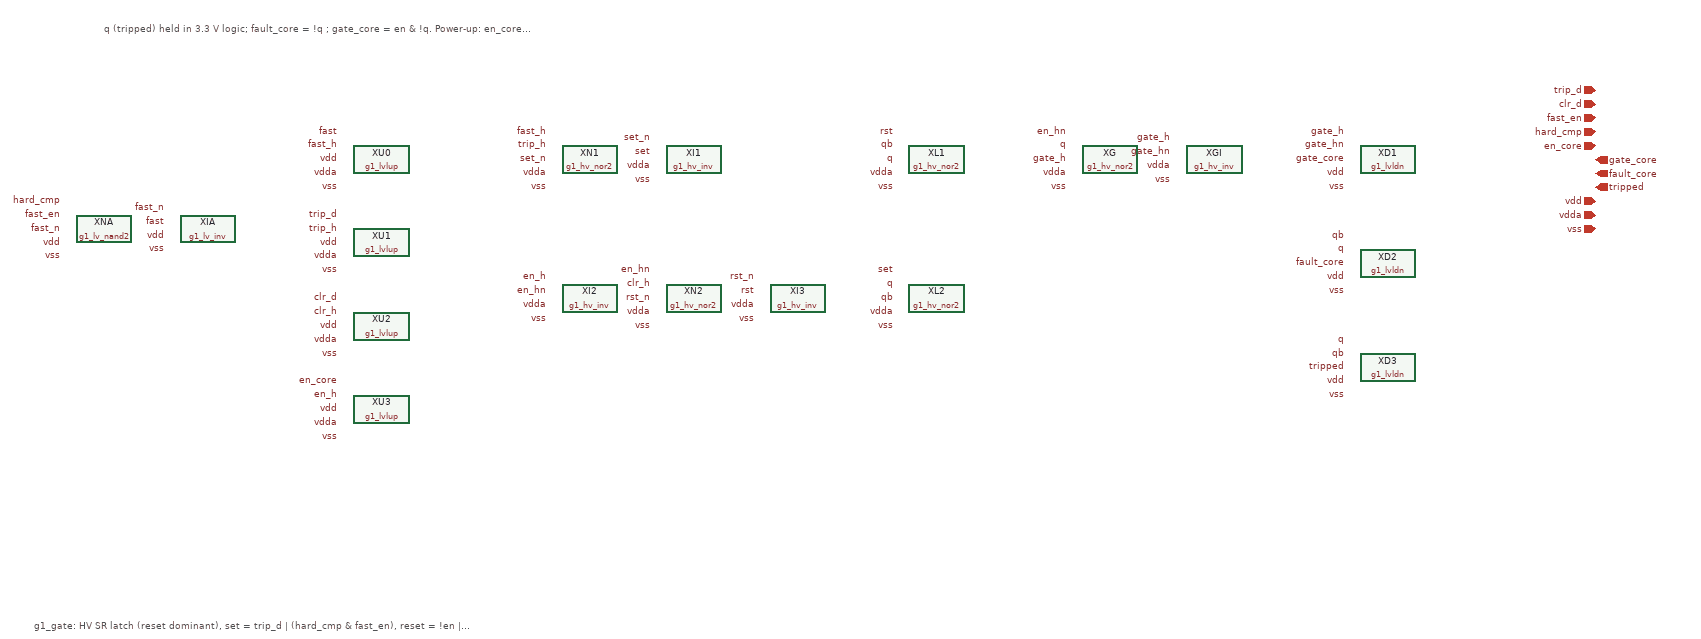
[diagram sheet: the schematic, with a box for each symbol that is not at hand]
v {xschem version=3.4.8RC file_version=1.3}
G {}
K {}
V {}
S {}
E {}
T {g1_gate: HV SR latch (reset dominant), set = trip_d | (hard_cmp & fast_en), reset = !en | clr_d} 0 -40 0 0 0.4 0.4 {}
C {g1_lv_nand2.sym} 100 -600 0 0 {name=XNA }
C {devices/lab_pin.sym} 40 -640 0 0 {name=l1 lab=hard_cmp}
C {devices/lab_pin.sym} 40 -620 0 0 {name=l2 lab=fast_en}
C {devices/lab_pin.sym} 40 -600 0 0 {name=l3 lab=fast_n}
C {devices/lab_pin.sym} 40 -580 0 0 {name=l4 lab=vdd}
C {devices/lab_pin.sym} 40 -560 0 0 {name=l5 lab=vss}
C {g1_lv_inv.sym} 250 -600 0 0 {name=XIA }
C {devices/lab_pin.sym} 190 -630 0 0 {name=l6 lab=fast_n}
C {devices/lab_pin.sym} 190 -610 0 0 {name=l7 lab=fast}
C {devices/lab_pin.sym} 190 -590 0 0 {name=l8 lab=vdd}
C {devices/lab_pin.sym} 190 -570 0 0 {name=l9 lab=vss}
C {g1_lvlup.sym} 500 -700 0 0 {name=XU0 }
C {devices/lab_pin.sym} 440 -740 0 0 {name=l10 lab=fast}
C {devices/lab_pin.sym} 440 -720 0 0 {name=l11 lab=fast_h}
C {devices/lab_pin.sym} 440 -700 0 0 {name=l12 lab=vdd}
C {devices/lab_pin.sym} 440 -680 0 0 {name=l13 lab=vdda}
C {devices/lab_pin.sym} 440 -660 0 0 {name=l14 lab=vss}
C {g1_lvlup.sym} 500 -580 0 0 {name=XU1 }
C {devices/lab_pin.sym} 440 -620 0 0 {name=l15 lab=trip_d}
C {devices/lab_pin.sym} 440 -600 0 0 {name=l16 lab=trip_h}
C {devices/lab_pin.sym} 440 -580 0 0 {name=l17 lab=vdd}
C {devices/lab_pin.sym} 440 -560 0 0 {name=l18 lab=vdda}
C {devices/lab_pin.sym} 440 -540 0 0 {name=l19 lab=vss}
C {g1_lvlup.sym} 500 -460 0 0 {name=XU2 }
C {devices/lab_pin.sym} 440 -500 0 0 {name=l20 lab=clr_d}
C {devices/lab_pin.sym} 440 -480 0 0 {name=l21 lab=clr_h}
C {devices/lab_pin.sym} 440 -460 0 0 {name=l22 lab=vdd}
C {devices/lab_pin.sym} 440 -440 0 0 {name=l23 lab=vdda}
C {devices/lab_pin.sym} 440 -420 0 0 {name=l24 lab=vss}
C {g1_lvlup.sym} 500 -340 0 0 {name=XU3 }
C {devices/lab_pin.sym} 440 -380 0 0 {name=l25 lab=en_core}
C {devices/lab_pin.sym} 440 -360 0 0 {name=l26 lab=en_h}
C {devices/lab_pin.sym} 440 -340 0 0 {name=l27 lab=vdd}
C {devices/lab_pin.sym} 440 -320 0 0 {name=l28 lab=vdda}
C {devices/lab_pin.sym} 440 -300 0 0 {name=l29 lab=vss}
C {g1_hv_nor2.sym} 800 -700 0 0 {name=XN1 }
C {devices/lab_pin.sym} 740 -740 0 0 {name=l30 lab=fast_h}
C {devices/lab_pin.sym} 740 -720 0 0 {name=l31 lab=trip_h}
C {devices/lab_pin.sym} 740 -700 0 0 {name=l32 lab=set_n}
C {devices/lab_pin.sym} 740 -680 0 0 {name=l33 lab=vdda}
C {devices/lab_pin.sym} 740 -660 0 0 {name=l34 lab=vss}
C {g1_hv_inv.sym} 950 -700 0 0 {name=XI1 }
C {devices/lab_pin.sym} 890 -730 0 0 {name=l35 lab=set_n}
C {devices/lab_pin.sym} 890 -710 0 0 {name=l36 lab=set}
C {devices/lab_pin.sym} 890 -690 0 0 {name=l37 lab=vdda}
C {devices/lab_pin.sym} 890 -670 0 0 {name=l38 lab=vss}
C {g1_hv_inv.sym} 800 -500 0 0 {name=XI2 }
C {devices/lab_pin.sym} 740 -530 0 0 {name=l39 lab=en_h}
C {devices/lab_pin.sym} 740 -510 0 0 {name=l40 lab=en_hn}
C {devices/lab_pin.sym} 740 -490 0 0 {name=l41 lab=vdda}
C {devices/lab_pin.sym} 740 -470 0 0 {name=l42 lab=vss}
C {g1_hv_nor2.sym} 950 -500 0 0 {name=XN2 }
C {devices/lab_pin.sym} 890 -540 0 0 {name=l43 lab=en_hn}
C {devices/lab_pin.sym} 890 -520 0 0 {name=l44 lab=clr_h}
C {devices/lab_pin.sym} 890 -500 0 0 {name=l45 lab=rst_n}
C {devices/lab_pin.sym} 890 -480 0 0 {name=l46 lab=vdda}
C {devices/lab_pin.sym} 890 -460 0 0 {name=l47 lab=vss}
C {g1_hv_inv.sym} 1100 -500 0 0 {name=XI3 }
C {devices/lab_pin.sym} 1040 -530 0 0 {name=l48 lab=rst_n}
C {devices/lab_pin.sym} 1040 -510 0 0 {name=l49 lab=rst}
C {devices/lab_pin.sym} 1040 -490 0 0 {name=l50 lab=vdda}
C {devices/lab_pin.sym} 1040 -470 0 0 {name=l51 lab=vss}
C {g1_hv_nor2.sym} 1300 -700 0 0 {name=XL1 }
C {devices/lab_pin.sym} 1240 -740 0 0 {name=l52 lab=rst}
C {devices/lab_pin.sym} 1240 -720 0 0 {name=l53 lab=qb}
C {devices/lab_pin.sym} 1240 -700 0 0 {name=l54 lab=q}
C {devices/lab_pin.sym} 1240 -680 0 0 {name=l55 lab=vdda}
C {devices/lab_pin.sym} 1240 -660 0 0 {name=l56 lab=vss}
C {g1_hv_nor2.sym} 1300 -500 0 0 {name=XL2 }
C {devices/lab_pin.sym} 1240 -540 0 0 {name=l57 lab=set}
C {devices/lab_pin.sym} 1240 -520 0 0 {name=l58 lab=q}
C {devices/lab_pin.sym} 1240 -500 0 0 {name=l59 lab=qb}
C {devices/lab_pin.sym} 1240 -480 0 0 {name=l60 lab=vdda}
C {devices/lab_pin.sym} 1240 -460 0 0 {name=l61 lab=vss}
C {g1_hv_nor2.sym} 1550 -700 0 0 {name=XG }
C {devices/lab_pin.sym} 1490 -740 0 0 {name=l62 lab=en_hn}
C {devices/lab_pin.sym} 1490 -720 0 0 {name=l63 lab=q}
C {devices/lab_pin.sym} 1490 -700 0 0 {name=l64 lab=gate_h}
C {devices/lab_pin.sym} 1490 -680 0 0 {name=l65 lab=vdda}
C {devices/lab_pin.sym} 1490 -660 0 0 {name=l66 lab=vss}
C {g1_hv_inv.sym} 1700 -700 0 0 {name=XGI }
C {devices/lab_pin.sym} 1640 -730 0 0 {name=l67 lab=gate_h}
C {devices/lab_pin.sym} 1640 -710 0 0 {name=l68 lab=gate_hn}
C {devices/lab_pin.sym} 1640 -690 0 0 {name=l69 lab=vdda}
C {devices/lab_pin.sym} 1640 -670 0 0 {name=l70 lab=vss}
C {g1_lvldn.sym} 1950 -700 0 0 {name=XD1 }
C {devices/lab_pin.sym} 1890 -740 0 0 {name=l71 lab=gate_h}
C {devices/lab_pin.sym} 1890 -720 0 0 {name=l72 lab=gate_hn}
C {devices/lab_pin.sym} 1890 -700 0 0 {name=l73 lab=gate_core}
C {devices/lab_pin.sym} 1890 -680 0 0 {name=l74 lab=vdd}
C {devices/lab_pin.sym} 1890 -660 0 0 {name=l75 lab=vss}
C {g1_lvldn.sym} 1950 -550 0 0 {name=XD2 }
C {devices/lab_pin.sym} 1890 -590 0 0 {name=l76 lab=qb}
C {devices/lab_pin.sym} 1890 -570 0 0 {name=l77 lab=q}
C {devices/lab_pin.sym} 1890 -550 0 0 {name=l78 lab=fault_core}
C {devices/lab_pin.sym} 1890 -530 0 0 {name=l79 lab=vdd}
C {devices/lab_pin.sym} 1890 -510 0 0 {name=l80 lab=vss}
C {g1_lvldn.sym} 1950 -400 0 0 {name=XD3 }
C {devices/lab_pin.sym} 1890 -440 0 0 {name=l81 lab=q}
C {devices/lab_pin.sym} 1890 -420 0 0 {name=l82 lab=qb}
C {devices/lab_pin.sym} 1890 -400 0 0 {name=l83 lab=tripped}
C {devices/lab_pin.sym} 1890 -380 0 0 {name=l84 lab=vdd}
C {devices/lab_pin.sym} 1890 -360 0 0 {name=l85 lab=vss}
C {devices/ipin.sym} 2250 -800 0 0 {name=pi0 lab=trip_d}
C {devices/ipin.sym} 2250 -780 0 0 {name=pi1 lab=clr_d}
C {devices/ipin.sym} 2250 -760 0 0 {name=pi2 lab=fast_en}
C {devices/ipin.sym} 2250 -740 0 0 {name=pi3 lab=hard_cmp}
C {devices/ipin.sym} 2250 -720 0 0 {name=pi4 lab=en_core}
C {devices/opin.sym} 2250 -700 0 0 {name=po0 lab=gate_core}
C {devices/opin.sym} 2250 -680 0 0 {name=po1 lab=fault_core}
C {devices/opin.sym} 2250 -660 0 0 {name=po2 lab=tripped}
C {devices/iopin.sym} 2250 -640 0 0 {name=pb0 lab=vdd}
C {devices/iopin.sym} 2250 -620 0 0 {name=pb1 lab=vdda}
C {devices/iopin.sym} 2250 -600 0 0 {name=pb2 lab=vss}
T {q (tripped) held in 3.3 V logic; fault_core = !q ; gate_core = en & !q. Power-up: en_core=0 forces gate_core=0.} 100 -900 0 0 0.3 0.3 {}
